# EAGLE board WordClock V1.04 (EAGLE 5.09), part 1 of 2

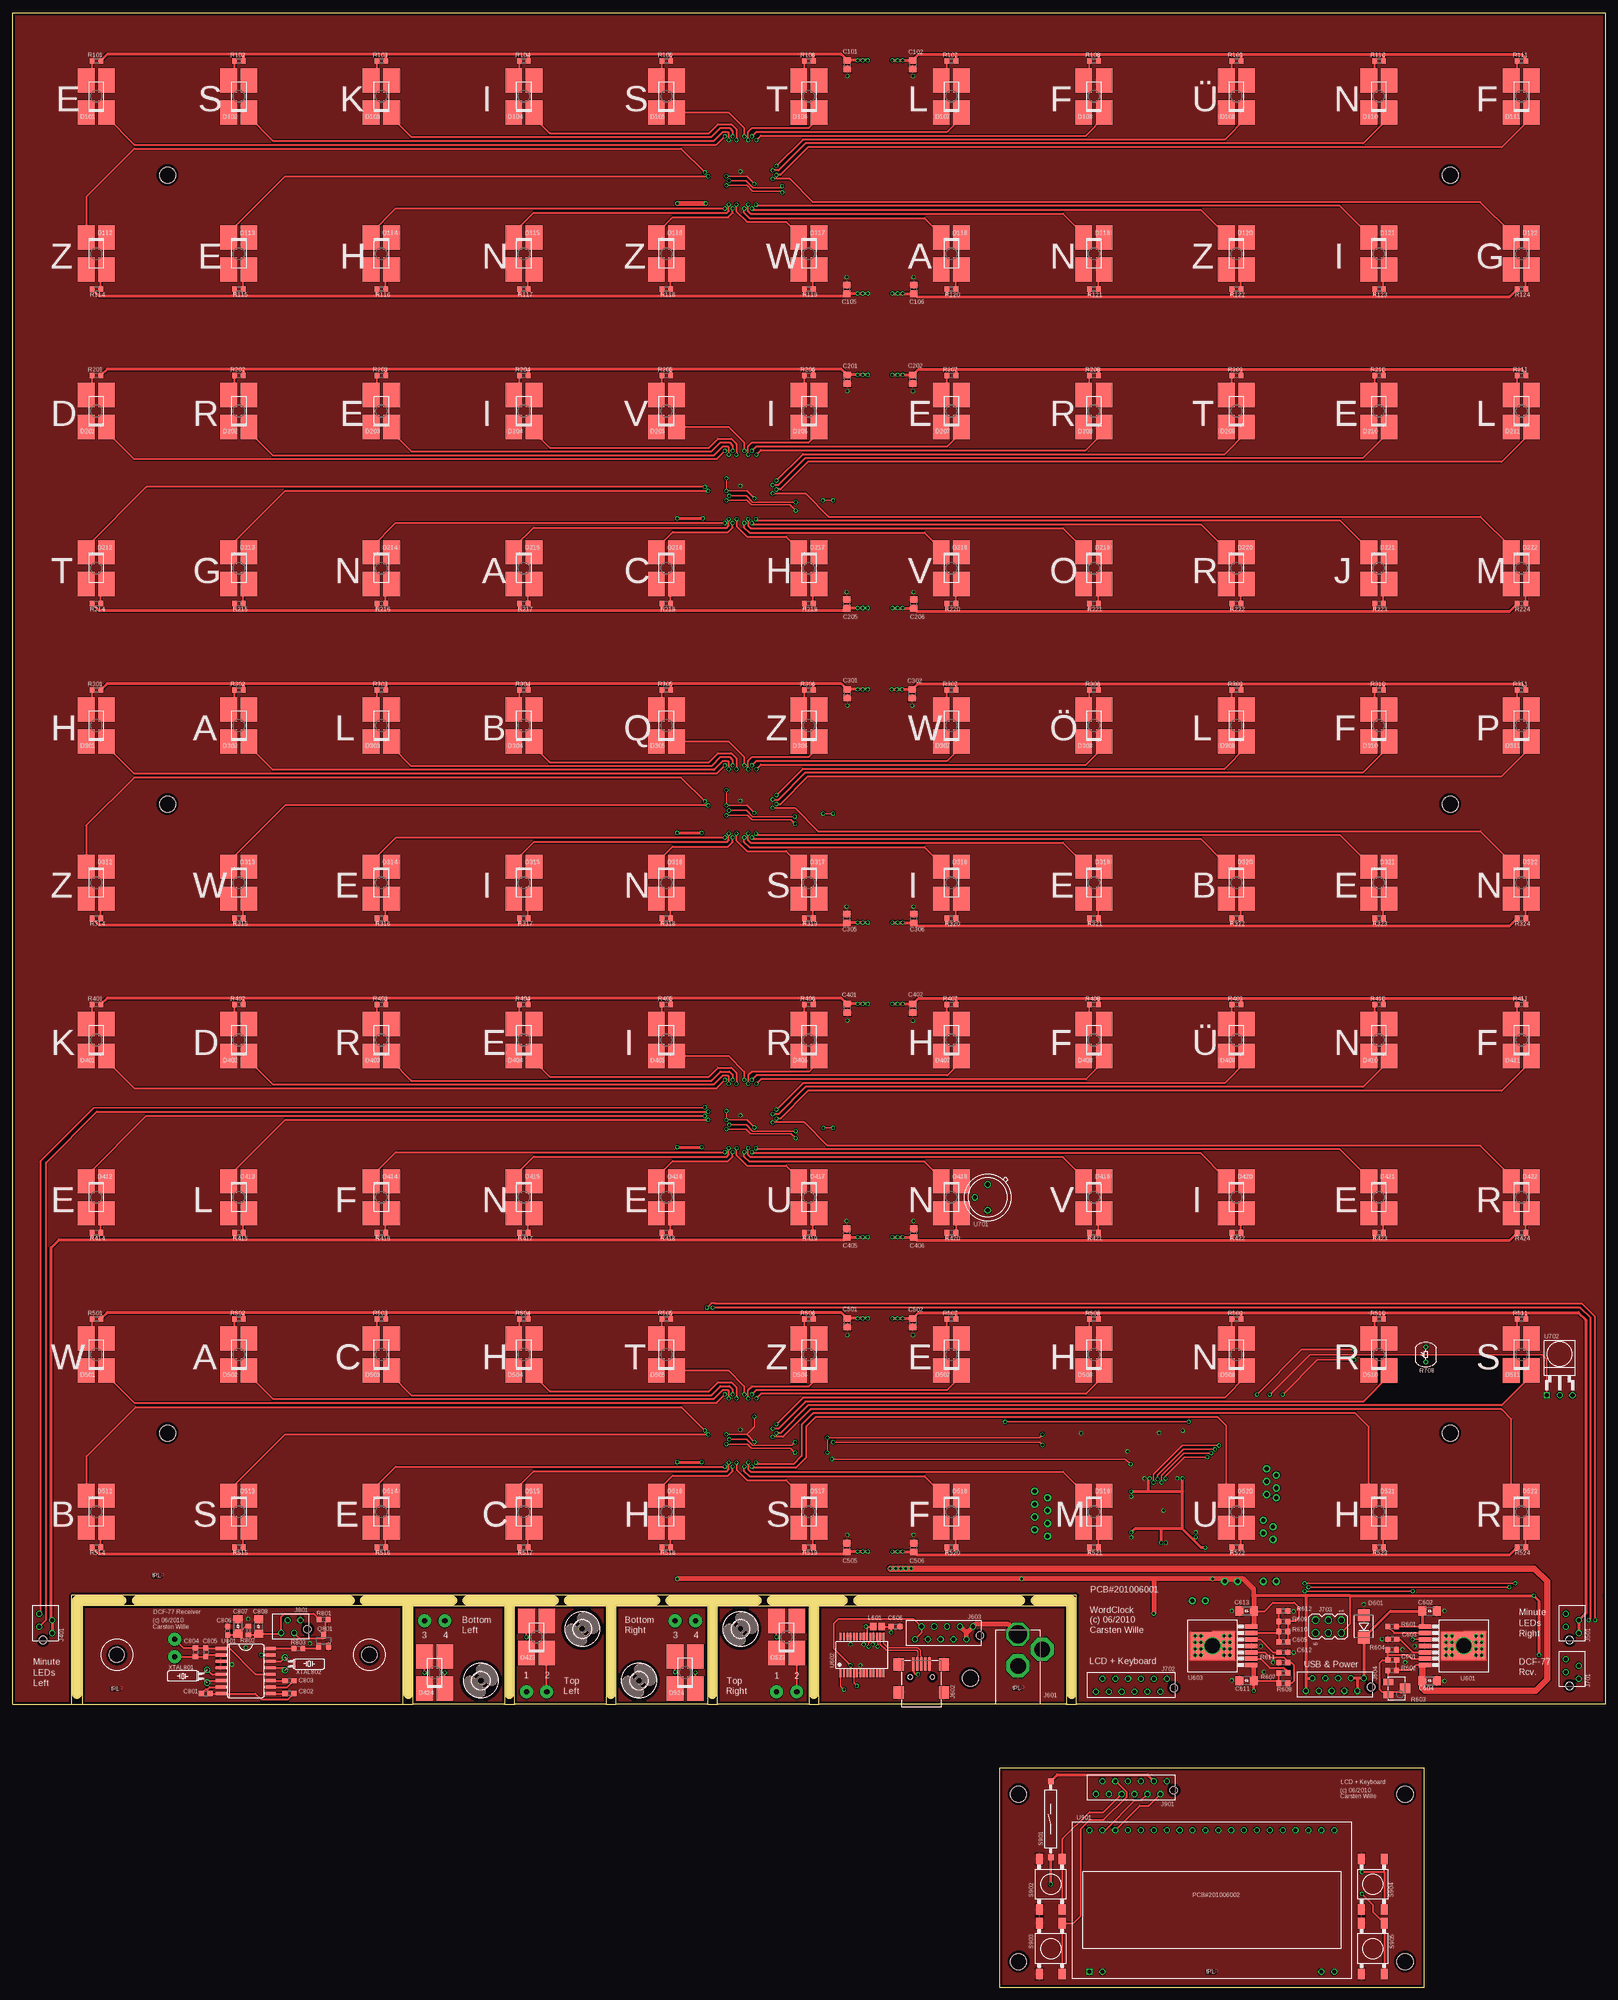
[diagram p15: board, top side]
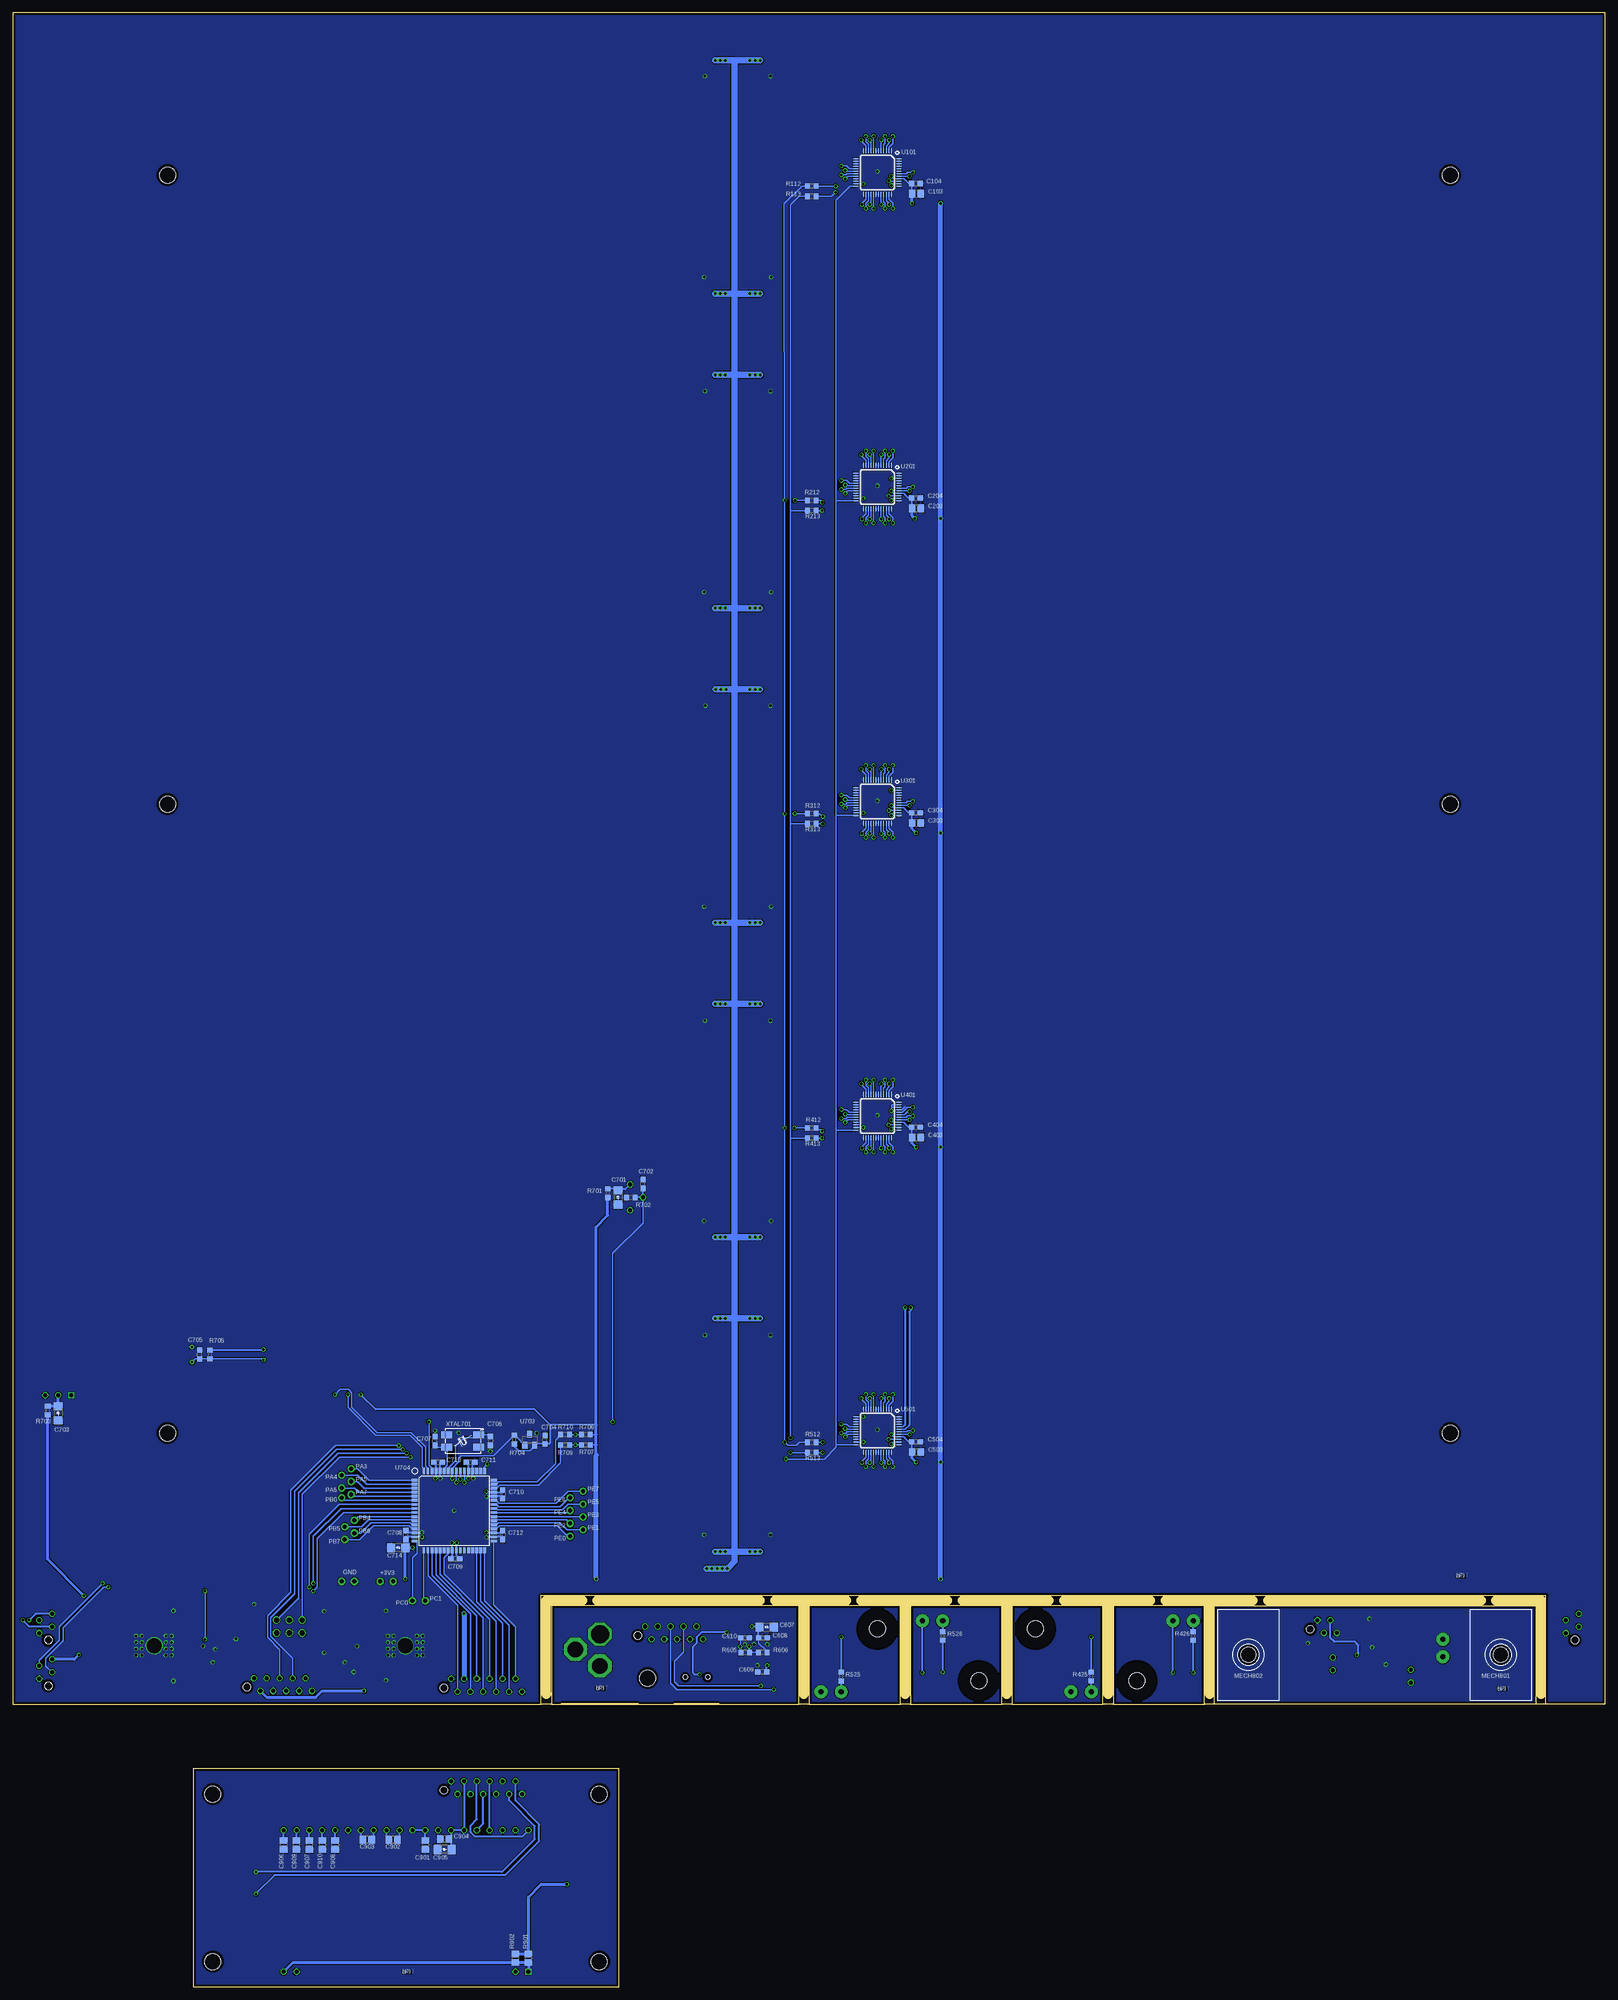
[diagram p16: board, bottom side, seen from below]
Size 314 x 389.24 mm. Coordinates in mm from the lower left corner, seen from the top.
Outline: 194.54,0 278.36,0 278.36,43.18 194.54,43.18 194.54,0
Copper layers (1*16): Top 0.035mm / dielectric 1.5mm / Bottom 0.035mm
Design rules "leiton": minimum track width 6mil, minimum drill 12mil, track to track 6mil, track to pad 6mil, pad to pad 6mil, via to via 6mil, smd to smd 6mil, copper to edge 20mil, drill to drill 8mil, minimum pad ring 8mil, minimum via ring 6mil, stop-mask expansion 3mil, vias tented up to drill 0mil, thermal gap 8mil
Holes 3.2 mm at 188.82,60.96 198.35,38.1 198.35,5.08 274.55,38.1 274.55,5.08

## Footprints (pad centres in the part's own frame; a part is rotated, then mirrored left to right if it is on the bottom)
C0805 = smd 1.3 x 1.5: 1 -0.85,0; 2 0.85,0
C0603 = smd 1.1 x 1: 1 -0.85,0; 2 0.85,0
C1206 = smd 1.6 x 1.8: 1 -1.4,0; 2 1.4,0
P-LCC-2 = smd 3.3 x 4.8: A -2,3.15; C 2,-3.15; NC@0 2,3.15; NC@1 -2,-3.15
SMB = smd 2.4 x 2.4: A 2.2,0; C -2.2,0
3,2 = hole 3.2: 0,0
MICRO-MATCH-4 = drill 0.8 round: 1 -1.905,-1.27; 2 -0.635,1.27; 3 0.635,-1.27; 4 1.905,1.27 | hole 1.5: -3.305,0.53
RAPC722X = drill 3.556 pad 4.572 octagon: 1 0,13.741 | drill 3.048 pad 4.572 octagon: 2 0,7.493; 3 4.801,10.744
USB-MINI-B-SMD = smd 2.6 x 0.5: 1 2.6,1.6; 2 2.6,0.8; 3 2.6,0; 4 2.6,-0.8; 5 2.6,-1.6 | smd 2.5 x 2: S0 -3,4.45; S1 2.5,4.45; S2 2.5,-4.45; S3 -3,-4.45 | hole 0.9: 0,2.2; 0,-2.2
MICRO-MATCH-10 = drill 0.8 round: 1 -5.715,-1.27; 2 -4.445,1.27; 3 -3.175,-1.27; 4 -1.905,1.27; 5 -0.635,-1.27; 6 0.635,1.27; 7 1.905,-1.27; 8 3.175,1.27; 9 4.445,-1.27; 10 5.715,1.27 | hole 1.5: -7.115,0.53
MICRO-MATCH-12 = drill 0.8 round: 1 -6.985,-1.27; 2 -5.715,1.27; 3 -4.445,-1.27; 4 -3.175,1.27; 5 -1.905,-1.27; 6 -0.635,1.27; 7 0.635,-1.27; 8 1.905,1.27; 9 3.175,-1.27; 10 4.445,1.27; 11 5.715,-1.27; 12 6.985,1.27 | hole 1.5: -8.385,0.53
MA03-2 = drill 1.016 round: 1 -1.27,2.54 | drill 1.016 octagon: 2 1.27,2.54; 3 -1.27,0; 4 1.27,0; 5 -1.27,-2.54; 6 1.27,-2.54
L0805 = smd 1.3 x 1.5: 1 -0.85,0; 2 0.85,0
SOCKET = hole 3: 0,0
WORDCLOCK_S = hole 3.2: 281.95,30.5; 29.05,278.5; 29.05,30.5; 281.95,278.5; 29.05,154.5; 281.95,154.5
SOT23 = smd 1 x 1.4: 1 -0.95,-1.1; 2 0.95,-1.1; 3 0,1.1
R0603 = smd 1 x 1.1: 1 -0.85,0; 2 0.85,0
RTRIM3224W = smd 1.3 x 2: 1 -1.25,-1.65; 3 1.25,-1.65 | smd 2 x 2: 2 0,1.65
LDR_A90 = drill 0.5 round: 1 -1.5,0; 2 1.5,0
R0805@1 = smd 1.3 x 1.5: 1 -0.85,0; 2 0.85,0
MK16-X-2 = smd 1.2 x 1.2: 1 -7.5,0; 2 7.5,0
LSH1301 = smd 2.1 x 1.4: 1 -5,2.25; 2 5,2.25; 3 -5,-2.25; 4 5,-2.25
LQFP48 = smd 0.203 x 1: 1 -2.75,-4.25; 2 -2.25,-4.25; 3 -1.75,-4.25; 4 -1.25,-4.25; 5 -0.75,-4.25; 6 -0.25,-4.25; 7 0.25,-4.25; 8 0.75,-4.25; 9 1.25,-4.25; 10 1.75,-4.25; 11 2.25,-4.25; 12 2.75,-4.25; 25 2.75,4.25; 26 2.25,4.25; 27 1.75,4.25; 28 1.25,4.25; 29 0.75,4.25; 30 0.25,4.25; 31 -0.25,4.25; 32 -0.75,4.25; 33 -1.25,4.25; 34 -1.75,4.25; 35 -2.25,4.25; 36 -2.75,4.25 | smd 1 x 0.203: 13 4.25,-2.75; 14 4.25,-2.25; 15 4.25,-1.75; 16 4.25,-1.25; 17 4.25,-0.75; 18 4.25,-0.25; 19 4.25,0.25; 20 4.25,0.75; 21 4.25,1.25; 22 4.25,1.75; 23 4.25,2.25; 24 4.25,2.75; 37 -4.25,2.75; 38 -4.25,2.25; 39 -4.25,1.75; 40 -4.25,1.25; 41 -4.25,0.75; 42 -4.25,0.25; 43 -4.25,-0.25; 44 -4.25,-0.75; 45 -4.25,-1.25; 46 -4.25,-1.75; 47 -4.25,-2.25; 48 -4.25,-2.75
TO-PMOD-7HS = smd 0.89 x 2.41: 1 -3.81,-7.63; 2 -2.54,-7.63; 3 -1.27,-7.63; 4 0,-7.63; 5 1.27,-7.63; 6 2.54,-7.63; 7 3.81,-7.63 | smd 5.35 x 8.54: HS 0,0
SSOP28 = smd 0.4 x 1.5: 1 -4.225,-3.625; 2 -3.575,-3.625; 3 -2.925,-3.625; 4 -2.275,-3.625; 5 -1.625,-3.625; 6 -0.975,-3.625; 7 -0.325,-3.625; 8 0.325,-3.625; 9 0.975,-3.625; 10 1.625,-3.625; 11 2.275,-3.625; 12 2.925,-3.625; 13 3.575,-3.625; 14 4.225,-3.625; 15 4.225,3.625; 16 3.575,3.625; 17 2.925,3.625; 18 2.275,3.625; 19 1.625,3.625; 20 0.975,3.625; 21 0.325,3.625; 22 -0.325,3.625; 23 -0.975,3.625; 24 -1.625,3.625; 25 -2.275,3.625; 26 -2.925,3.625; 27 -3.575,3.625; 28 -4.225,3.625
TO-5 = drill 0.813 octagon: 1 0,-2.54; 2 2.54,0; 3 0,2.54
TSOP322 = drill 0.8 square: 1 -2.54,-2.54 | drill 0.8 round: 2 0,-2.54; 3 2.54,-2.54
TQFP64 = smd 1.194 x 0.559: 1 -7.8,6; 2 -7.8,5.2; 3 -7.8,4.4; 4 -7.8,3.6; 5 -7.8,2.8; 6 -7.8,2; 7 -7.8,1.2; 8 -7.8,0.4; 9 -7.8,-0.4; 10 -7.8,-1.2; 11 -7.8,-2; 12 -7.8,-2.8; 13 -7.8,-3.6; 14 -7.8,-4.4; 15 -7.8,-5.2; 16 -7.8,-6; 33 7.8,-6; 34 7.8,-5.2; 35 7.8,-4.4; 36 7.8,-3.6; 37 7.8,-2.8; 38 7.8,-2; 39 7.8,-1.2; 40 7.8,-0.4; 41 7.8,0.4; 42 7.8,1.2; 43 7.8,2; 44 7.8,2.8; 45 7.8,3.6; 46 7.8,4.4; 47 7.8,5.2; 48 7.8,6 | smd 0.559 x 1.194: 17 -6,-7.8; 18 -5.2,-7.8; 19 -4.4,-7.8; 20 -3.6,-7.8; 21 -2.8,-7.8; 22 -2,-7.8; 23 -1.2,-7.8; 24 -0.4,-7.8; 25 0.4,-7.8; 26 1.2,-7.8; 27 2,-7.8; 28 2.8,-7.8; 29 3.6,-7.8; 30 4.4,-7.8; 31 5.2,-7.8; 32 6,-7.8; 49 6,7.8; 50 5.2,7.8; 51 4.4,7.8; 52 3.6,7.8; 53 2.8,7.8; 54 2,7.8; 55 1.2,7.8; 56 0.4,7.8; 57 -0.4,7.8; 58 -1.2,7.8; 59 -2,7.8; 60 -2.8,7.8; 61 -3.6,7.8; 62 -4.4,7.8; 63 -5.2,7.8; 64 -6,7.8
SO16L = smd 0.66 x 2.032: 1 -4.445,-4.902; 2 -3.175,-4.902; 3 -1.905,-4.902; 4 -0.635,-4.902; 5 0.635,-4.902; 6 1.905,-4.902; 7 3.175,-4.902; 8 4.445,-4.902; 9 4.445,4.902; 10 3.175,4.902; 11 1.905,4.902; 12 0.635,4.902; 13 -0.635,4.902; 14 -1.905,4.902; 15 -3.175,4.902; 16 -4.445,4.902
EA_DOGM132-5 = drill 0.8 square: 1 -24.13,-12.19 | drill 0.8 round: 2 -21.59,-12.19; 19 21.59,-12.19; 20 24.13,-12.19; 21 24.13,15.75; 22 21.59,15.75; 23 19.05,15.75; 24 16.51,15.75; 25 13.97,15.75; 26 11.43,15.75; 27 8.89,15.75; 28 6.35,15.75; 29 3.81,15.75; 30 1.27,15.75; 31 -1.27,15.75; 32 -3.81,15.75; 33 -6.35,15.75; 34 -8.89,15.75; 35 -11.43,15.75; 36 -13.97,15.75; 37 -16.51,15.75; 38 -19.05,15.75; 39 -21.59,15.75; 40 -24.13,15.75
SINGLE-PIN = drill 0.813 pad 1.422 round: P$1 0,0
SINGLE-PIN_BIG = drill 1.016 pad 2.54 round: 1 0,0
MQ = smd 2.2 x 1.4: 1 -3.15,-1.25; 2 3.15,-1.25; 3 3.15,1.25; 4 -3.15,1.25
TC26H = drill 0.813 round: 1 -1.27,0; 2 1.27,0

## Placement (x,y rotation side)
C101  1E-6-1U-0805  [C0805]  164.57,378.99 270 top
C102  1E-6-1U-0805  [C0805]  177.46,378.99 270 top
C103  1E-6-1U-0805  [C0805]  135.81,353.54 0 bottom
C104  1E-9-100N-0603  [C0603]  135.88,355.57 0 bottom
C105  1E-6-1U-0805  [C0805]  164.47,334.69 90 top
C106  1E-6-1U-0805  [C0805]  177.69,334.69 90 top
C201  1E-6-1U-0805  [C0805]  164.57,316.99 270 top
C202  1E-6-1U-0805  [C0805]  177.46,316.99 270 top
C203  1E-6-1U-0805  [C0805]  135.81,291.54 0 bottom
C204  1E-9-100N-0603  [C0603]  135.88,293.57 0 bottom
C205  1E-6-1U-0805  [C0805]  164.47,272.69 90 top
C206  1E-6-1U-0805  [C0805]  177.69,272.69 90 top
C301  1E-6-1U-0805  [C0805]  164.57,254.99 270 top
C302  1E-6-1U-0805  [C0805]  177.33,254.99 270 top
C303  1E-6-1U-0805  [C0805]  135.81,229.54 0 bottom
C304  1E-9-100N-0603  [C0603]  135.88,231.57 0 bottom
C305  1E-6-1U-0805  [C0805]  164.47,210.69 90 top
C306  1E-6-1U-0805  [C0805]  177.69,210.69 90 top
C401  1E-6-1U-0805  [C0805]  164.57,192.99 270 top
C402  1E-6-1U-0805  [C0805]  177.46,192.99 270 top
C403  1E-6-1U-0805  [C0805]  135.81,167.54 0 bottom
C404  1E-9-100N-0603  [C0603]  135.88,169.57 0 bottom
C405  1E-6-1U-0805  [C0805]  164.47,148.69 90 top
C406  1E-6-1U-0805  [C0805]  177.69,148.69 90 top
C501  1E-6-1U-0805  [C0805]  164.57,130.99 270 top
C502  1E-6-1U-0805  [C0805]  177.46,130.99 270 top
C503  1E-6-1U-0805  [C0805]  135.81,105.54 0 bottom
C504  1E-9-100N-0603  [C0603]  135.88,107.57 0 bottom
C505  1E-6-1U-0805  [C0805]  164.47,86.69 90 top
C506  1E-6-1U-0805  [C0805]  177.69,86.69 90 top
C601  1E-9-22N-0603  [C0603]  272.01,64.52 180 top
C602  1E-6-10U-1206  [C1206]  279.38,74.17 0 top
C603  1E-9-22N-0603  [C0603]  272.01,68.58 180 top
C604  1E-6-10U-1206  [C1206]  279.38,60.45 0 top
C605  1E-9-22N-0603  [C0603]  250.55,68.07 180 top
C606  1E-9-10N-0603  [C0603]  174.09,71.12 0 top
C607  1E-6-10U-1206  [C1206]  165.33,70.99 0 bottom
C608  1E-9-100N-0603  [C0603]  166.07,68.91 0 bottom
C609  1E-9-100N-0603  [C0603]  166.19,62.15 180 bottom
C610  1E-9-100N-0603  [C0603]  169.57,68.91 0 bottom
C611  1E-6-10U-1206  [C1206]  243.31,60.45 180 top
C612  1E-9-22N-0603  [C0603]  250.55,66.04 0 top
C613  1E-6-10U-1206  [C1206]  243.31,74.17 180 top
C701  1E-6-10U-1206  [C1206]  194.67,155.7 270 bottom
C702  1E-9-33N-0603  [C0603]  189.71,158.37 90 bottom
C703  1E-6-10U-1206  [C1206]  305.03,113.16 270 bottom
C704  1E-9-100N-0603  [C0603]  209.02,107.95 90 bottom
C705  1E-9-33N-0603  [C0603]  277.14,124.74 90 bottom
C706  1E-12-22P-0603  [C0603]  219.81,107.7 270 bottom
C707  1E-12-22P-0603  [C0603]  230.74,107.7 90 bottom
C708  1E-9-100N-0603  [C0603]  236.48,89.18 90 bottom
C709  1E-9-100N-0603  [C0603]  226.72,84.45 180 bottom
C710  1E-9-100N-0603  [C0603]  217.37,97.18 270 bottom
C711  1E-9-100N-0603  [C0603]  223.72,103.53 0 bottom
C712  1E-9-100N-0603  [C0603]  217.37,89.18 270 bottom
C713  1E-9-100N-0603  [C0603]  230.13,103.53 0 bottom
C714  1E-6-10U-1206  [C1206]  237.97,86.66 180 bottom
C801  1E-9-6.8N-0603  [C0603]  38.08,57.91 0 top
C802  1E-9-33N-0603  [C0603]  54.59,57.91 180 top
C803  1E-9-10N-0603  [C0603]  54.59,60.45 180 top
C804  1E-9-1.5N-0603  [C0603]  36.04,66.04 270 top
C805  1E-9-1.5N-0603  [C0603]  38.08,66.04 270 top
C806  1E-9-100N-0603  [C0603]  42.39,70.31 90 top
C807  1E-6-10U-1206  [C1206]  44.43,71.15 90 top
C808  1E-6-10U-1206  [C1206]  48.49,71.12 90 top
C901  1E-6-1U-0805  [C0805]  232.64,28.07 270 bottom
C902  1E-6-1U-0805  [C0805]  238.99,29.08 180 bottom
C903  1E-6-1U-0805  [C0805]  244.07,29.08 180 bottom
C904  1E-6-1U-0805  [C0805]  228.83,29.21 180 bottom
C905  1E-6-10U-1206  [C1206]  228.83,27.18 180 bottom
C906  1E-6-1U-0805  [C0805]  260.58,28.07 270 bottom
C907  1E-6-1U-0805  [C0805]  255.5,28.07 270 bottom
C908  1E-6-1U-0805  [C0805]  250.42,28.07 270 bottom
C909  1E-6-1U-0805  [C0805]  258.04,28.07 270 bottom
C910  1E-6-1U-0805  [C0805]  252.96,28.07 270 bottom
D101  TOPLED-LUW  [P-LCC-2]  16.5,372.74 0 top
D102  TOPLED-LUW  [P-LCC-2]  44.6,372.74 0 top
D103  TOPLED-LUW  [P-LCC-2]  72.7,372.74 0 top
D104  TOPLED-LUW  [P-LCC-2]  100.8,372.74 0 top
D105  TOPLED-LUW  [P-LCC-2]  128.9,372.74 0 top
D106  TOPLED-LUW  [P-LCC-2]  157,372.74 0 top
D107  TOPLED-LUW  [P-LCC-2]  185.1,372.74 0 top
D108  TOPLED-LUW  [P-LCC-2]  213.2,372.74 0 top
D109  TOPLED-LUW  [P-LCC-2]  241.3,372.74 0 top
D110  TOPLED-LUW  [P-LCC-2]  269.4,372.74 0 top
D111  TOPLED-LUW  [P-LCC-2]  297.5,372.74 0 top
D112  TOPLED-LUW  [P-LCC-2]  16.5,341.74 180 top
D113  TOPLED-LUW  [P-LCC-2]  44.6,341.74 180 top
D114  TOPLED-LUW  [P-LCC-2]  72.7,341.74 180 top
D115  TOPLED-LUW  [P-LCC-2]  100.8,341.74 180 top
D116  TOPLED-LUW  [P-LCC-2]  128.9,341.74 180 top
D117  TOPLED-LUW  [P-LCC-2]  157,341.74 180 top
D118  TOPLED-LUW  [P-LCC-2]  185.1,341.74 180 top
D119  TOPLED-LUW  [P-LCC-2]  213.2,341.74 180 top
D120  TOPLED-LUW  [P-LCC-2]  241.3,341.74 180 top
D121  TOPLED-LUW  [P-LCC-2]  269.4,341.74 180 top
D122  TOPLED-LUW  [P-LCC-2]  297.5,341.74 180 top
D201  TOPLED-LUW  [P-LCC-2]  16.5,310.74 0 top
D202  TOPLED-LUW  [P-LCC-2]  44.6,310.74 0 top
D203  TOPLED-LUW  [P-LCC-2]  72.7,310.74 0 top
D204  TOPLED-LUW  [P-LCC-2]  100.8,310.74 0 top
D205  TOPLED-LUW  [P-LCC-2]  128.9,310.74 0 top
D206  TOPLED-LUW  [P-LCC-2]  157,310.74 0 top
D207  TOPLED-LUW  [P-LCC-2]  185.1,310.74 0 top
D208  TOPLED-LUW  [P-LCC-2]  213.2,310.74 0 top
D209  TOPLED-LUW  [P-LCC-2]  241.3,310.74 0 top
D210  TOPLED-LUW  [P-LCC-2]  269.4,310.74 0 top
D211  TOPLED-LUW  [P-LCC-2]  297.5,310.74 0 top
D212  TOPLED-LUW  [P-LCC-2]  16.5,279.74 180 top
D213  TOPLED-LUW  [P-LCC-2]  44.6,279.74 180 top
D214  TOPLED-LUW  [P-LCC-2]  72.7,279.74 180 top
D215  TOPLED-LUW  [P-LCC-2]  100.8,279.74 180 top
D216  TOPLED-LUW  [P-LCC-2]  128.9,279.74 180 top
D217  TOPLED-LUW  [P-LCC-2]  157,279.74 180 top
D218  TOPLED-LUW  [P-LCC-2]  185.1,279.74 180 top
D219  TOPLED-LUW  [P-LCC-2]  213.2,279.74 180 top
D220  TOPLED-LUW  [P-LCC-2]  241.3,279.74 180 top
D221  TOPLED-LUW  [P-LCC-2]  269.4,279.74 180 top
D222  TOPLED-LUW  [P-LCC-2]  297.5,279.74 180 top
D301  TOPLED-LUW  [P-LCC-2]  16.5,248.74 0 top
D302  TOPLED-LUW  [P-LCC-2]  44.6,248.74 0 top
D303  TOPLED-LUW  [P-LCC-2]  72.7,248.74 0 top
D304  TOPLED-LUW  [P-LCC-2]  100.8,248.74 0 top
D305  TOPLED-LUW  [P-LCC-2]  128.9,248.74 0 top
D306  TOPLED-LUW  [P-LCC-2]  157,248.74 0 top
D307  TOPLED-LUW  [P-LCC-2]  185.1,248.74 0 top
D308  TOPLED-LUW  [P-LCC-2]  213.2,248.74 0 top
D309  TOPLED-LUW  [P-LCC-2]  241.3,248.74 0 top
D310  TOPLED-LUW  [P-LCC-2]  269.4,248.74 0 top
D311  TOPLED-LUW  [P-LCC-2]  297.5,248.74 0 top
D312  TOPLED-LUW  [P-LCC-2]  16.5,217.74 180 top
D313  TOPLED-LUW  [P-LCC-2]  44.6,217.74 180 top
D314  TOPLED-LUW  [P-LCC-2]  72.7,217.74 180 top
D315  TOPLED-LUW  [P-LCC-2]  100.8,217.74 180 top
D316  TOPLED-LUW  [P-LCC-2]  128.9,217.74 180 top
D317  TOPLED-LUW  [P-LCC-2]  157,217.74 180 top
D318  TOPLED-LUW  [P-LCC-2]  185.1,217.74 180 top
D319  TOPLED-LUW  [P-LCC-2]  213.2,217.74 180 top
D320  TOPLED-LUW  [P-LCC-2]  241.3,217.74 180 top
D321  TOPLED-LUW  [P-LCC-2]  269.4,217.74 180 top
D322  TOPLED-LUW  [P-LCC-2]  297.5,217.74 180 top
D401  TOPLED-LUW  [P-LCC-2]  16.5,186.74 0 top
D402  TOPLED-LUW  [P-LCC-2]  44.6,186.74 0 top
D403  TOPLED-LUW  [P-LCC-2]  72.7,186.74 0 top
D404  TOPLED-LUW  [P-LCC-2]  100.8,186.74 0 top
D405  TOPLED-LUW  [P-LCC-2]  128.9,186.74 0 top
D406  TOPLED-LUW  [P-LCC-2]  157,186.74 0 top
D407  TOPLED-LUW  [P-LCC-2]  185.1,186.74 0 top
D408  TOPLED-LUW  [P-LCC-2]  213.2,186.74 0 top
D409  TOPLED-LUW  [P-LCC-2]  241.3,186.74 0 top
D410  TOPLED-LUW  [P-LCC-2]  269.4,186.74 0 top
D411  TOPLED-LUW  [P-LCC-2]  297.5,186.74 0 top
D412  TOPLED-LUW  [P-LCC-2]  16.5,155.74 180 top
D413  TOPLED-LUW  [P-LCC-2]  44.6,155.74 180 top
D414  TOPLED-LUW  [P-LCC-2]  72.7,155.74 180 top
D415  TOPLED-LUW  [P-LCC-2]  100.8,155.74 180 top
D416  TOPLED-LUW  [P-LCC-2]  128.9,155.74 180 top
D417  TOPLED-LUW  [P-LCC-2]  157,155.74 180 top
D418  TOPLED-LUW  [P-LCC-2]  185.1,155.74 180 top
D419  TOPLED-LUW  [P-LCC-2]  213.2,155.74 180 top
D420  TOPLED-LUW  [P-LCC-2]  241.3,155.74 180 top
D421  TOPLED-LUW  [P-LCC-2]  269.4,155.74 180 top
D422  TOPLED-LUW  [P-LCC-2]  297.5,155.74 180 top
D423  TOPLED-LUW  [P-LCC-2]  103.31,69.04 0 top
D424  TOPLED-LUW  [P-LCC-2]  83.21,62.04 0 top
D501  TOPLED-LUW  [P-LCC-2]  16.5,124.74 0 top
D502  TOPLED-LUW  [P-LCC-2]  44.6,124.74 0 top
D503  TOPLED-LUW  [P-LCC-2]  72.7,124.74 0 top
D504  TOPLED-LUW  [P-LCC-2]  100.8,124.74 0 top
D505  TOPLED-LUW  [P-LCC-2]  128.9,124.74 0 top
D506  TOPLED-LUW  [P-LCC-2]  157,124.74 0 top
D507  TOPLED-LUW  [P-LCC-2]  185.1,124.74 0 top
D508  TOPLED-LUW  [P-LCC-2]  213.2,124.74 0 top
D509  TOPLED-LUW  [P-LCC-2]  241.3,124.74 0 top
D510  TOPLED-LUW  [P-LCC-2]  269.4,124.74 0 top
D511  TOPLED-LUW  [P-LCC-2]  297.5,124.74 0 top
D512  TOPLED-LUW  [P-LCC-2]  16.5,93.74 180 top
D513  TOPLED-LUW  [P-LCC-2]  44.6,93.74 180 top
D514  TOPLED-LUW  [P-LCC-2]  72.7,93.74 180 top
D515  TOPLED-LUW  [P-LCC-2]  100.8,93.74 180 top
D516  TOPLED-LUW  [P-LCC-2]  128.9,93.74 180 top
D517  TOPLED-LUW  [P-LCC-2]  157,93.74 180 top
D518  TOPLED-LUW  [P-LCC-2]  185.1,93.74 180 top
D519  TOPLED-LUW  [P-LCC-2]  213.2,93.74 180 top
D520  TOPLED-LUW  [P-LCC-2]  241.3,93.74 180 top
D521  TOPLED-LUW  [P-LCC-2]  269.4,93.74 180 top
D522  TOPLED-LUW  [P-LCC-2]  297.5,93.74 180 top
D523  TOPLED-LUW  [P-LCC-2]  152.61,69.04 0 top
D524  TOPLED-LUW  [P-LCC-2]  132.6,62.06 0 top
D601  20BQ030-SMB  [SMB]  266.42,71.12 90 top
H401  MOUNT-HOLE3.2  [3,2]  92.31,60.44 0 top
H402  MOUNT-HOLE3.2  [3,2]  112.31,70.64 0 top
H501  MOUNT-HOLE3.2  [3,2]  123.51,60.44 0 top
H502  MOUNT-HOLE3.2  [3,2]  143.51,70.64 0 top
J401  MICRO-MATCH-4  [MICRO-MATCH-4]  6.5,71.74 90 top
J501  MICRO-MATCH-4  [MICRO-MATCH-4]  307.5,71.74 90 top
J601  PWR-JACK  [RAPC722X]  198.22,55.88 0 top
J602  USB_B_MINI  [USB-MINI-B-SMD]  179.17,61.14 90 top
J603  MICRO-MATCH-10  [MICRO-MATCH-10]  183.62,69.85 180 top
J604  MICRO-MATCH-10  [MICRO-MATCH-10]  260.71,59.69 180 top
J701  MICRO-MATCH-4  [MICRO-MATCH-4]  307.5,62.74 90 top
J702  MICRO-MATCH-12  [MICRO-MATCH-12]  220.57,59.56 180 top
J703  PROG-PDI  [MA03-2]  259.44,71.12 270 top
J801  MICRO-MATCH-4  [MICRO-MATCH-4]  54.84,71.12 180 top
J901  MICRO-MATCH-12  [MICRO-MATCH-12]  220.57,39.37 180 top
L601  L-1U0-0805  [L0805]  170.54,71.12 180 top
MECH801  SOCKET  [SOCKET]  20.55,65.53 0 bottom
MECH802  SOCKET  [SOCKET]  70.33,65.53 0 bottom
PCB1  PCB-WORDCLOCK-ALL-IN-ONE  [WORDCLOCK_S]  1.5,78.74 0 top
Q801  BC847  [SOT23]  61.32,68.33 0 top
R101  1E0-3,0R-0603  [R0603]  16.5,379.74 180 top
R102  1E0-3,0R-0603  [R0603]  44.6,379.74 180 top
R103  1E0-3,0R-0603  [R0603]  72.7,379.74 180 top
R104  1E0-3,0R-0603  [R0603]  100.8,379.74 180 top
R105  1E0-3,0R-0603  [R0603]  128.9,379.74 180 top
R106  1E0-3,0R-0603  [R0603]  157,379.74 180 top
R107  1E0-3,0R-0603  [R0603]  185.1,379.74 180 top
R108  1E0-3,0R-0603  [R0603]  213.2,379.74 180 top
R109  1E0-3,0R-0603  [R0603]  241.3,379.74 180 top
R110  1E0-3,0R-0603  [R0603]  269.4,379.74 180 top
R111  1E0-3,0R-0603  [R0603]  297.5,379.74 180 top
R112  1E2-330R-0603  [R0603]  156.44,355.07 0 bottom
R113  1E2-330R-0603  [R0603]  156.44,353.06 0 bottom
R114  1E0-3,0R-0603  [R0603]  16.5,334.74 180 top
R115  1E0-3,0R-0603  [R0603]  44.6,334.74 180 top
R116  1E0-3,0R-0603  [R0603]  72.7,334.74 180 top
R117  1E0-3,0R-0603  [R0603]  100.8,334.74 180 top
R118  1E0-3,0R-0603  [R0603]  128.9,334.74 180 top
R119  1E0-3,0R-0603  [R0603]  157,334.74 180 top
R120  1E0-3,0R-0603  [R0603]  185.1,334.74 180 top
R121  1E0-3,0R-0603  [R0603]  213.2,334.74 180 top
R122  1E0-3,0R-0603  [R0603]  241.3,334.74 180 top
R123  1E0-3,0R-0603  [R0603]  269.4,334.74 180 top
R124  1E0-3,0R-0603  [R0603]  297.5,334.74 180 top
R201  1E0-3,0R-0603  [R0603]  16.5,317.74 180 top
R202  1E0-3,0R-0603  [R0603]  44.6,317.74 180 top
R203  1E0-3,0R-0603  [R0603]  72.7,317.74 180 top
R204  1E0-3,0R-0603  [R0603]  100.8,317.74 180 top
R205  1E0-3,0R-0603  [R0603]  128.9,317.74 180 top
R206  1E0-3,0R-0603  [R0603]  157,317.74 180 top
R207  1E0-3,0R-0603  [R0603]  185.1,317.74 180 top
R208  1E0-3,0R-0603  [R0603]  213.2,317.74 180 top
R209  1E0-3,0R-0603  [R0603]  241.3,317.74 180 top
R210  1E0-3,0R-0603  [R0603]  269.4,317.74 180 top
R211  1E0-3,0R-0603  [R0603]  297.5,317.74 180 top
R212  1E2-330R-0603  [R0603]  156.44,293.12 0 bottom
R213  1E2-330R-0603  [R0603]  156.44,291.08 0 bottom
R214  1E0-3,0R-0603  [R0603]  16.5,272.74 180 top
R215  1E0-3,0R-0603  [R0603]  44.6,272.74 180 top
R216  1E0-3,0R-0603  [R0603]  72.7,272.74 180 top
R217  1E0-3,0R-0603  [R0603]  100.8,272.74 180 top
R218  1E0-3,0R-0603  [R0603]  128.9,272.74 180 top
R219  1E0-3,0R-0603  [R0603]  157,272.74 180 top
R220  1E0-3,0R-0603  [R0603]  185.1,272.74 180 top
R221  1E0-3,0R-0603  [R0603]  213.2,272.74 180 top
R222  1E0-3,0R-0603  [R0603]  241.3,272.74 180 top
R223  1E0-3,0R-0603  [R0603]  269.4,272.74 180 top
R224  1E0-3,0R-0603  [R0603]  297.5,272.74 180 top
R301  1E0-3,0R-0603  [R0603]  16.5,255.74 180 top
R302  1E0-3,0R-0603  [R0603]  44.6,255.74 180 top
R303  1E0-3,0R-0603  [R0603]  72.7,255.74 180 top
R304  1E0-3,0R-0603  [R0603]  100.8,255.74 180 top
R305  1E0-3,0R-0603  [R0603]  128.9,255.74 180 top
R306  1E0-3,0R-0603  [R0603]  157,255.74 180 top
R307  1E0-3,0R-0603  [R0603]  185.1,255.74 180 top
R308  1E0-3,0R-0603  [R0603]  213.2,255.74 180 top
R309  1E0-3,0R-0603  [R0603]  241.3,255.74 180 top
R310  1E0-3,0R-0603  [R0603]  269.4,255.74 180 top
R311  1E0-3,0R-0603  [R0603]  297.5,255.74 180 top
R312  1E2-330R-0603  [R0603]  156.44,231.37 0 bottom
R313  1E2-330R-0603  [R0603]  156.44,229.36 0 bottom
R314  1E0-3,0R-0603  [R0603]  16.5,210.74 180 top
R315  1E0-3,0R-0603  [R0603]  44.6,210.74 180 top
R316  1E0-3,0R-0603  [R0603]  72.7,210.74 180 top
R317  1E0-3,0R-0603  [R0603]  100.8,210.74 180 top
R318  1E0-3,0R-0603  [R0603]  128.9,210.74 180 top
R319  1E0-3,0R-0603  [R0603]  157,210.74 180 top
R320  1E0-3,0R-0603  [R0603]  185.1,210.74 180 top
R321  1E0-3,0R-0603  [R0603]  213.2,210.74 180 top
R322  1E0-3,0R-0603  [R0603]  241.3,210.74 180 top
R323  1E0-3,0R-0603  [R0603]  269.4,210.74 180 top
R324  1E0-3,0R-0603  [R0603]  297.5,210.74 180 top
R401  1E0-3,0R-0603  [R0603]  16.5,193.74 180 top
R402  1E0-3,0R-0603  [R0603]  44.6,193.74 180 top
R403  1E0-3,0R-0603  [R0603]  72.7,193.74 180 top
R404  1E0-3,0R-0603  [R0603]  100.8,193.74 180 top
R405  1E0-3,0R-0603  [R0603]  128.9,193.74 180 top
R406  1E0-3,0R-0603  [R0603]  157,193.74 180 top
R407  1E0-3,0R-0603  [R0603]  185.1,193.74 180 top
R408  1E0-3,0R-0603  [R0603]  213.2,193.74 180 top
R409  1E0-3,0R-0603  [R0603]  241.3,193.74 180 top
R410  1E0-3,0R-0603  [R0603]  269.4,193.74 180 top
R411  1E0-3,0R-0603  [R0603]  297.5,193.74 180 top
R412  1E2-330R-0603  [R0603]  156.44,169.42 0 bottom
R413  1E2-330R-0603  [R0603]  156.44,167.39 0 bottom
R414  1E0-3,0R-0603  [R0603]  16.5,148.74 180 top
R415  1E0-3,0R-0603  [R0603]  44.6,148.74 180 top
R416  1E0-3,0R-0603  [R0603]  72.7,148.74 180 top
R417  1E0-3,0R-0603  [R0603]  100.8,148.74 180 top
R418  1E0-3,0R-0603  [R0603]  128.9,148.74 180 top
R419  1E0-3,0R-0603  [R0603]  157,148.74 180 top
R420  1E0-3,0R-0603  [R0603]  185.1,148.74 180 top
R421  1E0-3,0R-0603  [R0603]  213.2,148.74 180 top
R422  1E0-3,0R-0603  [R0603]  241.3,148.74 180 top
R423  1E0-3,0R-0603  [R0603]  269.4,148.74 180 top
R424  1E0-3,0R-0603  [R0603]  297.5,148.74 180 top
R425  1E0-3,0R-0603  [R0603]  101.31,61.24 90 bottom
R426  1E0-3,0R-0603  [R0603]  81.21,69.24 270 bottom
R501  1E0-3,0R-0603  [R0603]  16.5,131.74 180 top
R502  1E0-3,0R-0603  [R0603]  44.6,131.74 180 top
R503  1E0-3,0R-0603  [R0603]  72.7,131.74 180 top
R504  1E0-3,0R-0603  [R0603]  100.8,131.74 180 top
R505  1E0-3,0R-0603  [R0603]  128.9,131.74 180 top
R506  1E0-3,0R-0603  [R0603]  157,131.74 180 top
R507  1E0-3,0R-0603  [R0603]  185.1,131.74 180 top
R508  1E0-3,0R-0603  [R0603]  213.2,131.74 180 top
R509  1E0-3,0R-0603  [R0603]  241.3,131.74 180 top
R510  1E0-3,0R-0603  [R0603]  269.4,131.74 180 top
R511  1E0-3,0R-0603  [R0603]  297.5,131.74 180 top
R512  1E2-330R-0603  [R0603]  156.44,107.44 0 bottom
R513  1E2-330R-0603  [R0603]  156.44,105.41 0 bottom
R514  1E0-3,0R-0603  [R0603]  16.5,86.74 180 top
R515  1E0-3,0R-0603  [R0603]  44.6,86.74 180 top
R516  1E0-3,0R-0603  [R0603]  72.7,86.74 180 top
R517  1E0-3,0R-0603  [R0603]  100.8,86.74 180 top
R518  1E0-3,0R-0603  [R0603]  128.9,86.74 180 top
R519  1E0-3,0R-0603  [R0603]  157,86.74 180 top
R520  1E0-3,0R-0603  [R0603]  185.1,86.74 180 top
R521  1E0-3,0R-0603  [R0603]  213.2,86.74 180 top
R522  1E0-3,0R-0603  [R0603]  241.3,86.74 180 top
R523  1E0-3,0R-0603  [R0603]  269.4,86.74 180 top
R524  1E0-3,0R-0603  [R0603]  297.5,86.74 180 top
R525  1E0-3,0R-0603  [R0603]  150.59,61.23 90 bottom
R526  1E0-3,0R-0603  [R0603]  130.61,69.24 270 bottom
R601  1E4-56K-0603  [R0603]  272.01,71.12 180 top
R602  1E3-3,3K-0603  [R0603]  272.01,62.48 180 top
R603  R-TRIM1K-3224W  [RTRIM3224W]  272.9,58.93 270 top
R604  1E3-1,1K-0603  [R0603]  272.01,66.55 0 top
R605  1E4-10K-0603  [R0603]  169.57,66.04 0 bottom
R606  1E3-4,7K-0603  [R0603]  166.12,66.04 180 bottom
R607  1E4-47K-0603  [R0603]  250.55,61.98 0 top
R608  1E4-33K-0603  [R0603]  250.55,59.94 0 top
R609  1E4-13K-0603  [R0603]  250.55,72.14 180 top
R610  1E3-4,7K-0603  [R0603]  250.55,70.1 180 top
R611  1E4-12K-0603  [R0603]  250.55,64.01 180 top
R612  1E3-1,1K-0603  [R0603]  250.55,74.17 0 top
R701  1E2-100R-0603  [R0603]  196.67,156.54 90 bottom
R702  1E4-47K-0603  [R0603]  192.13,155.7 180 bottom
R703  1E2-100R-0603  [R0603]  307.09,113.72 90 bottom
R704  1E4-10K-0603  [R0603]  215.11,107.95 90 bottom
R705  1E4-10K-0603  [R0603]  275.13,124.74 270 bottom
R706  1E3-3,3K-0603  [R0603]  201.02,108.94 180 bottom
R707  1E3-3,3K-0603  [R0603]  201.02,106.91 180 bottom
R708  LDR  [LDR_A90]  278.64,124.74 90 top
R709  1E2-330R-0603  [R0603]  205.08,106.91 180 bottom
R710  1E2-330R-0603  [R0603]  205.08,108.94 180 bottom
R801  1E4-10K-0603  [R0603]  61.32,72.52 0 top
R802  1E2-100R-0603  [R0603]  46.46,70.31 270 top
R803  1E5-100K-0603  [R0603]  56.36,66.8 0 top
R901  1E0-3,3R-0805  [R0805@1]  212.32,5.71 270 bottom
R902  1E0-3,3R-0805  [R0805@1]  214.86,5.71 270 bottom
S901  MK16-SERIES  [MK16-X-2]  204.7,33.15 90 top
S902  LSH1301-9,5  [LSH1301]  204.7,20.32 90 top
S903  LSH1301-9,5  [LSH1301]  204.7,7.62 90 top
S904  LSH1301-9,5  [LSH1301]  268.2,20.32 90 top
S905  LSH1301-9,5  [LSH1301]  268.2,7.62 90 top
U101  PCA9626  [LQFP48]  143.5,357.74 180 bottom
U201  PCA9626  [LQFP48]  143.5,295.74 180 bottom
U301  PCA9626  [LQFP48]  143.5,233.74 180 bottom
U401  PCA9626  [LQFP48]  143.5,171.74 180 bottom
U501  PCA9626  [LQFP48]  143.5,109.74 180 bottom
U601  LMZ12003  [TO-PMOD-7HS]  286.11,67.31 270 top
U602  FT232RL  [SSOP28]  167.49,65.53 0 top
U603  LMZ12003  [TO-PMOD-7HS]  236.58,67.31 90 top
U701  LHI1128  [TO-5]  192.25,155.7 180 top
U702  TSOP32236  [TSOP322]  305.03,119.25 0 top
U703  MCP120  [SOT23]  212.07,107.95 0 bottom
U704  XMEGA64A3  [TQFP64]  226.93,93.98 0 bottom
U801  U4224B  [SO16L]  45.95,62.36 270 top
U901  EA_DOGM132B-5  [EA_DOGM132-5]  236.45,15.24 0 top
X1  SINGLE-PIN-36MIL  [SINGLE-PIN]  204.06,88.9 180 top
X2  SINGLE-PIN-36MIL  [SINGLE-PIN]  201.53,90.17 180 top
X3  SINGLE-PIN-36MIL  [SINGLE-PIN]  204.06,91.44 180 top
X4  SINGLE-PIN-36MIL  [SINGLE-PIN]  201.53,92.71 180 top
X5  SINGLE-PIN-36MIL  [SINGLE-PIN]  204.06,93.98 180 top
X6  SINGLE-PIN-36MIL  [SINGLE-PIN]  201.53,95.25 180 top
X7  SINGLE-PIN-36MIL  [SINGLE-PIN]  204.06,96.52 180 top
X8  SINGLE-PIN-36MIL  [SINGLE-PIN]  201.53,97.79 180 top
X9  SINGLE-PIN-36MIL  [SINGLE-PIN]  247.25,102.23 0 top
X10  SINGLE-PIN-36MIL  [SINGLE-PIN]  249.15,100.97 0 top
X11  SINGLE-PIN-36MIL  [SINGLE-PIN]  247.25,99.69 0 top
X12  SINGLE-PIN-36MIL  [SINGLE-PIN]  249.15,98.42 0 top
X13  SINGLE-PIN-36MIL  [SINGLE-PIN]  247.25,97.16 0 top
X14  SINGLE-PIN-36MIL  [SINGLE-PIN]  249.15,96.52 0 top
X15  SINGLE-PIN-36MIL  [SINGLE-PIN]  246.61,92.07 0 top
X16  SINGLE-PIN-36MIL  [SINGLE-PIN]  248.51,90.8 0 top
X17  SINGLE-PIN-36MIL  [SINGLE-PIN]  246.61,89.53 0 top
X18  SINGLE-PIN-36MIL  [SINGLE-PIN]  248.51,88.27 0 top
X19  SINGLE-PIN-36MIL  [SINGLE-PIN]  235.18,76.2 0 top
X20  SINGLE-PIN-36MIL  [SINGLE-PIN]  232.64,76.2 0 top
X21  SINGLE-PIN-36MIL  [SINGLE-PIN]  246.61,80.01 90 top
X22  SINGLE-PIN-36MIL  [SINGLE-PIN]  249.15,80.01 90 top
X23  SINGLE-PIN-36MIL  [SINGLE-PIN]  241.53,80.01 90 top
X24  SINGLE-PIN-36MIL  [SINGLE-PIN]  238.99,80.01 90 top
X401  SINGLE-PIN-40MIL  [SINGLE-PIN_BIG]  101.31,58.24 90 top
X402  SINGLE-PIN-40MIL  [SINGLE-PIN_BIG]  81.21,72.24 90 top
X403  SINGLE-PIN-40MIL  [SINGLE-PIN_BIG]  105.31,58.24 90 top
X404  SINGLE-PIN-40MIL  [SINGLE-PIN_BIG]  85.21,72.24 90 top
X501  SINGLE-PIN-40MIL  [SINGLE-PIN_BIG]  150.61,58.24 90 top
X502  SINGLE-PIN-40MIL  [SINGLE-PIN_BIG]  130.61,72.24 90 top
X503  SINGLE-PIN-40MIL  [SINGLE-PIN_BIG]  154.61,58.24 90 top
X504  SINGLE-PIN-40MIL  [SINGLE-PIN_BIG]  134.61,72.24 90 top
X801  SINGLE-PIN-40MIL  [SINGLE-PIN_BIG]  31.98,68.58 270 top
X802  SINGLE-PIN-40MIL  [SINGLE-PIN_BIG]  31.98,65.15 270 top
XTAL701  MQ-8.000  [MQ]  225.27,107.7 180 bottom
XTAL801  TC26-77.5  [TC26H]  38.33,61.34 90 top
XTAL802  TC26-77.5  [TC26H]  53.7,63.75 270 top

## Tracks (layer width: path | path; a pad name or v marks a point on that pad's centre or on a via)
12V0  (via drill 0.5)
  Top 0.406: 244.71,63.37 244.33,63.37 U603.1 | 249.7,60.45 R608.1 | 249.7,60.45 R607.1 | C611.1 249.7,60.45 | R601.1 277.98,71.12 U601.1
  Top 0.61: 265.15,60.96 J604.2 | 265.15,60.96 J604.3 | 265.15,60.96 J604.1 D601.C 271.67,74.17 C602.1 277.98,71.12 | v244.71,58.42 C611.1
  Top 0.813: C611.1
  Top 1.016: C611.1 244.71,63.37
  Bottom 0.61: J604.2 263.88,57.15 254.23,57.15 252.96,58.42 v244.71,58.42
+3V3  (via drill 0.5)
  Top 0.254: v140.74,357 144.76,357 v146.26,355.49 | v146.26,293.49 144.76,295 v140.74,295 v140.74,297.43 | v146.26,231.49 144.76,233 v140.74,233 v140.74,235.97 | v146.26,169.49 144.76,171 v140.74,171 v140.74,172.75 | v140.74,109 144.76,109 | 144.76,109 v146.26,107.49 | v146.25,112.5 146.25,110.5 144.76,109 | X24.P$1 X23.P$1 241.53,80.52
  Top 0.406: C605.1 R610.1 R609.1 252.96,72.14 253.59,72.77 253.59,74.93 252.71,75.82 248.51,75.82 246.86,74.17 C613.1 | 244.71,71.5 244.59,71.5 U603.7 | v220.57,97.71 220.55,97.74 | 223.9,99.8 223.9,100.05 v224.18,100.33 | v264.52,125.73 254.23,125.73 v245.34,116.84 | J703.2 263.75,71.63 263.75,77.22
  Top 0.61: v131.04,289.56 v136.12,289.56 | v131.04,227.58 v135.87,227.58 | v131.04,165.61 v135.87,165.61 | v131.04,103.5 v135.87,103.5 | 254.99,77.22 263.75,77.22 v299.95,77.22 300.97,76.2 v300.97,65.53 | 254.99,77.22 244.71,77.22 | v235.16,86.66 234.37,86.66 232.78,88.25 | 230.66,97.71 v230.66,100.33 230.66,100.34 | 223.9,97.71 223.9,99.8 | 223.9,97.71 v220.57,97.71 | 230.66,97.71 223.9,97.71 | 232.78,88.25 230.66,90.37 | 230.66,90.37 230.66,97.71 | v220.57,89.69 221.26,90.37 226.42,90.37 | 230.66,90.37 226.42,90.37 | 226.42,90.37 v226.42,87.63 | 232.78,88.25 v233.28,88.72 | 254.99,77.22 254.99,60.96 | 254.99,60.96 J604.10 | 254.99,60.96 J604.9
  Top 1.016: v131.04,351.66 v136.65,351.66 | 225.02,80.52 v198.96,80.52 v131.04,80.52 | 225.02,80.52 v225.02,73.66 | 225.02,80.52 v236.58,80.52 241.53,80.52 242.67,80.52 244.71,78.49 244.71,77.22 C613.1 244.71,71.5
  Bottom 0.254: 138.15,356.36 138.28,356.49 U101.40 140.24,356.49 v140.74,357 | v146.26,355.49 U101.23 | 138.15,294.36 138.28,294.49 U201.40 140.24,294.49 v140.74,295 | v146.26,293.49 U201.23 | 138.15,232.36 138.28,232.49 U301.40 140.24,232.49 v140.74,233 | v146.26,231.49 U301.23 | 138.15,170.36 138.28,170.49 U401.40 140.24,170.49 v140.74,171 | v146.26,169.49 U401.23 | 138.15,108.36 138.28,108.49 U501.40 140.24,108.49 v140.74,109 | v146.26,107.49 U501.23 | U501.13 146.51,112.49 v146.25,112.5 | U401.47 140.49,173.99 140.74,173.74 140.74,173.49 | v140.74,235.97 140.67,235.99 U301.47 | U201.46 140.64,297.49 v140.74,297.43 | R704.1 215.11,106.68 214.22,105.79 211.94,105.79 211.12,106.61 U703.2 | R706.1 198.99,108.94 198.96,108.97 | R707.1 198.99,106.91 198.96,106.93 | 140.74,173.49 U401.46 | v140.74,172.75 140.74,173.49
  Bottom 0.406: 138.15,356.36 137.36,355.57 C104.1 136.66,355.5 C103.1 | 138.15,294.36 137.36,293.57 C204.1 136.66,293.5 C203.1 | 138.15,232.36 137.36,231.57 C304.1 136.66,231.5 C303.1 | 138.15,170.36 137.36,169.57 C404.1 136.66,169.5 C403.1 | 138.15,108.36 137.36,107.57 C504.1 136.66,107.49 C503.1 | U703.2 210.87,107.1 C704.1 208.22,107.1 208,107.31 208,110.87 | 198.96,110.87 208,110.87 | 208,110.87 211.05,113.92 242.42,113.92 v245.34,116.84 | C710.1 217.38,97.58 U704.45 220.44,97.58 v220.57,97.71 | C712.1 217.38,89.58 U704.35 220.47,89.58 v220.57,89.69 | C709.1 225.87,84.6 226.53,85.25 U704.25 226.53,87.52 v226.42,87.63 | C708.1 236.47,88.78 U704.15 233.36,88.78 v233.28,88.72 | C711.1 224.12,103.53 U704.53 224.12,100.33 v224.18,100.33 | C713.1 230.53,103.53 U704.61 230.53,100.46 v230.66,100.33 | R705.1 264.66,125.59 v264.52,125.73
  Bottom 0.61: v136.65,351.66 C103.1 | C203.1 136.66,290.1 v136.12,289.56 | C303.1 136.66,228.37 v135.87,227.58 | C403.1 136.66,166.4 v135.87,165.61 | C503.1 136.66,104.29 v135.87,103.5 | R701.1 196.67,152.17 198.99,149.86 198.96,110.87 198.96,108.97 198.96,106.93 198.96,104.9 | v300.97,65.53 301.85,64.64 J701.4 | v299.95,77.22 307.09,84.35 R703.1 | 236.42,86.66 v235.16,86.66 | 236.42,86.66 C714.1 | 236.42,86.66 236.58,86.51 v236.58,80.52
  Bottom 1.016: v131.04,351.66 v131.04,289.56 v131.04,227.58 v131.04,165.61 v131.04,103.5 v131.04,80.52 | v198.96,80.52 198.96,104.9 | v225.02,73.66 J702.3
+3V3A  (via drill 0.5)
  Top 0.406: J603.10 179.17,69.85 J603.9 177.65,72.64 162.79,72.64 161.9,71.75 161.9,66.78 v165.2,63.47 165.21,63.36 U602.4
  Bottom 0.406: C609.1 165.34,63.23 v165.2,63.47
A0
  Top 0.406: U901.38 222.22,35.81 224,35.81 J901.2
A+
  Bottom 0.61: U901.1 R901.2 R902.2 258.76,4.86 U901.20
BL
  Top 0.406: S903.3 S903.4 209.14,12.62 210.62,14.1 210.62,31.24 212.4,33.02 215.11,33.02 219.68,37.59 219.68,38.48 217.52,40.64 J901.9
BR  (via drill 0.5)
  Top 0.406: v266.04,18.41 268.2,16.26 268.2,14.87 S905.4 S905.3
  Bottom 0.406: J901.11 214.86,36.83 210.16,32.13 210.16,28.83 216.89,22.1 262.36,22.1 v266.04,18.41
CLK
  Bottom 0.406: U901.37 J901.7
CS#
  Bottom 0.406: U901.40 213.59,29.72 222.81,29.72 223.7,30.61 223.7,31.88 222.48,33.1 J901.5
D+
  Top 0.254: U602.15 171.71,67.78 172.57,66.93 178.54,66.93 179.05,66.42 179.05,65.41 179.17,65.28 J602.3
D-
  Top 0.254: U602.16 171.06,67.67 172.31,66.42 178.28,66.42 178.54,66.17 178.54,65.41 178.37,65.24 J602.2
DCF77  (via drill 0.5)
  Top 0.254: v255.5,78.87 v295.12,78.87
  Bottom 0.254: J701.2 307.44,63.32 307.44,64.9 304.01,68.33 304.01,70.87 296.01,78.87 v295.12,78.87 | v255.5,78.87 255.5,89.27 249.59,95.18 U704.7
DIN
  Bottom 0.406: J901.6 221.21,32.26 U901.36
DISP-A0
  Bottom 0.254: J702.2 226.29,75.31 232.12,81.15 U704.18
DISP-CLK
  Bottom 0.254: J702.7 219.94,72.52 228.96,81.53 228.96,84.63 228.12,85.46 U704.23
DISP-CS#
  Bottom 0.254: J702.5 222.48,73.28 230.53,81.32 U704.20
DISP-DIN
  Bottom 0.254: J702.6 221.21,72.9 229.72,81.41 U704.21
DISP-RESET#
  Bottom 0.254: J702.4 223.75,73.66 231.32,81.23 U704.19
GND  (via drill 0.5, 3)
  Top 0.406: U601.HS 286.11,70.05 290.48,70.05 290.48,64.54 281.76,64.54 281.76,70.05 286.03,70.05 | U603.HS 236.58,70.05 240.92,70.05 240.92,64.57 232.23,64.57 232.23,70.03 236.53,70.03
  Bottom 0.254: U401.45 138.64,172.99 138.03,173.61
  Bottom 0.406: C710.2 217.38,96.78 U704.44 220.52,96.78 v220.57,96.72 | C712.2 217.38,88.78 U704.34 220.49,88.78 v220.57,88.7 | C709.2 227.32,84.45 U704.24 227.32,87.57 v227.38,87.63 | C708.2 236.47,89.58 U704.14 233.38,89.58 v233.28,89.69 | C711.2 223.32,103.53 U704.52 223.32,100.33 v223.17,100.33 | C713.2 229.72,103.53 U704.60 229.72,100.41 v229.64,100.33
  other vias: 219.81,105.66 230.74,109.73 226.04,109.3 210.67,109.22 226.93,93.98 164.57,89.2 177.65,89.2 177.52,128.57 164.57,128.57 164.44,151.05 177.65,151.05 164.57,190.55 177.52,190.55 177.65,213.03 164.44,213.03 164.44,275.01 177.4,252.65 177.65,275.01 164.57,252.65 164.57,314.63 177.52,314.63 164.44,337.11 177.65,337.11 164.57,376.73 177.52,376.73 143.49,357.94 143.49,295.96 143.49,233.86 143.49,171.88 143.49,109.91 240.39,74.22 246.1,67.23 248.51,64.06 240.39,60.5 252.58,74.09 252.58,65.96 266.42,75.49 269.98,68.63 274.04,66.6 276.45,67.23 282.3,60.38 282.3,74.22 246.74,62.15 274.55,64.06 286.11,67.31 236.58,67.31 233.15,69.27 233.15,68 233.15,66.73 233.15,65.46 234.29,69.27 234.29,68 234.29,66.73 234.29,65.46 240.01,65.46 238.86,65.46 238.86,66.73 240.01,66.73 240.01,68 238.86,68 238.86,69.27 240.01,69.27 282.68,69.27 282.68,68 282.68,66.73 282.68,65.46 283.82,69.27 283.82,68 283.82,66.73 283.82,65.46 288.52,69.27 288.52,68 288.52,66.73 288.52,65.46 289.66,69.27 289.66,68 289.66,66.73 289.66,65.46
  pour Bottom: 0,389.23 314,389.23 314,55.85 209.78,55.85 209.78,77.24 11.66,77.24 11.66,55.88 0,55.88 0,77.24
  pour Top: 0,389.23 314,389.23 314,55.85 209.78,55.85 209.78,77.24 11.66,77.24 11.66,55.88 0,55.88 0,77.24
GND1  (via drill 0.5)
  other vias: 46.46,72.64 45.95,67.01 43.23,63.63 58.65,67.82
  pour Bottom: 13.69,75.18 13.69,55.88 77.06,55.88 77.06,75.18
  pour Top: 13.69,75.18 13.69,55.88 77.06,55.88 77.06,75.18
GND2
  pour Bottom: 194.54,43.18 194.54,0 278.36,0 278.36,43.18
  pour Top: 194.54,43.18 194.54,0 278.36,0 278.36,43.18
GNDA  (via drill 0.5)
  other vias: 165.2,67.59 167.82,67.59 169.62,67.59 167.16,63.47
  pour Bottom: 158.98,75.31 158.98,55.88 207.75,55.88 207.75,75.31
  pour Top: 158.98,75.31 158.98,55.88 207.75,55.88 207.75,75.31
IR  (via drill 0.5)
  Top 0.254: U702.1 302.49,123.82 301.6,124.71 255.75,124.71 v247.88,116.84
  Bottom 0.254: U704.64 232.93,102.27 233.3,102.64 233.3,106.49 235.65,108.84 242.42,108.84 247.88,114.3 v247.88,116.84
KEY0
  Bottom 0.254: J702.8 218.67,72.14 222.53,75.99 U704.30
KEY1
  Bottom 0.254: J702.9 217.4,71.75 221.72,76.08 U704.31
KEY2
  Bottom 0.254: J702.10 216.13,71.37 220.93,76.17 U704.32
KEY3
  Bottom 0.254: J702.11 214.86,71.12 219.12,75.38 U704.33
LDR  (via drill 0.5)
  Top 0.254: v264.52,123.7 257.28,123.7 v250.42,116.84
  Bottom 0.254: R708.1 277.99,123.89 C705.1 R705.2 264.71,123.89 v264.52,123.7 | U704.63 232.12,102.28 232.59,102.74 232.59,106.52 235.39,109.32 242.14,109.32 247.12,114.3 247.12,117.22 247.75,117.86 249.4,117.86 v250.42,116.84
LED0@U1  (via drill 0.5)
  Top 0.406: v140.44,364.87 138.79,363.22 23.98,363.22 18.52,368.68 18.52,369.57 D101.C
  Bottom 0.254: U101.2 141.25,362.71 140.44,363.53 v140.44,364.87
LED0@U2  (via drill 0.5)
  Top 0.406: v140.44,302.87 138.79,301.22 23.98,301.22 18.52,306.68 18.52,307.57 D201.C
  Bottom 0.254: U201.2 141.25,300.71 140.44,301.52 v140.44,302.87
LED0@U3  (via drill 0.5)
  Top 0.406: v140.44,240.87 138.79,239.22 23.98,239.22 18.52,244.68 18.52,245.57 D301.C
  Bottom 0.254: U301.2 141.25,238.71 140.44,239.52 v140.44,240.87
LED0@U4  (via drill 0.5)
  Top 0.406: v140.44,178.87 138.79,177.22 23.98,177.22 18.52,182.68 18.52,183.57 D401.C
  Bottom 0.254: U401.2 141.25,176.71 140.44,177.52 v140.44,178.87
LED0@U5  (via drill 0.5)
  Top 0.406: v140.44,116.87 138.79,115.22 23.98,115.22 18.52,120.68 18.52,121.57 D501.C
  Bottom 0.254: U501.2 141.25,114.71 140.44,115.52 v140.44,116.87
LED1@U1  (via drill 0.5)
  Top 0.406: v141.2,364.11 141.2,365.51 140.95,365.76 140.06,365.76 138.28,363.98 51.28,363.98 46.59,368.68 46.59,369.57 D102.C
  Bottom 0.254: U101.3 141.75,362.95 141.2,363.5 v141.2,364.11
LED1@U2  (via drill 0.5)
  Top 0.406: v141.2,302.11 141.2,303.51 140.95,303.76 140.06,303.76 138.28,301.98 51.28,301.98 46.59,306.68 46.59,307.57 D202.C
  Bottom 0.254: U201.3 141.75,300.95 141.2,301.5 v141.2,302.11
LED1@U3  (via drill 0.5)
  Top 0.406: v141.2,240.11 141.2,241.51 140.95,241.76 140.06,241.76 138.28,239.98 51.28,239.98 46.59,244.68 46.59,245.57 D302.C
  Bottom 0.254: U301.3 141.75,238.95 141.2,239.5 v141.2,240.11
LED1@U4  (via drill 0.5)
  Top 0.406: v141.2,178.11 141.2,179.51 140.95,179.76 140.06,179.76 138.28,177.98 51.28,177.98 46.59,182.68 46.59,183.57 D402.C
  Bottom 0.254: U401.3 141.75,176.95 141.2,177.5 v141.2,178.11
LED1@U5  (via drill 0.5)
  Top 0.406: v141.2,116.11 141.2,117.51 140.95,117.76 140.06,117.76 138.28,115.98 51.28,115.98 46.59,120.68 46.59,121.57 D502.C
  Bottom 0.254: U501.3 141.75,114.95 141.2,115.5 v141.2,116.11
LED2@U1  (via drill 0.5)
  Top 0.406: v141.96,364.87 141.96,365.89 141.33,366.52 139.55,366.52 137.77,364.74 78.59,364.74 74.78,368.55 74.78,369.51 D103.C
  Bottom 0.254: U101.4 142.25,363.19 141.96,363.47 v141.96,364.87
LED2@U2  (via drill 0.5)
  Top 0.406: v141.96,302.87 141.96,303.89 141.33,304.52 139.55,304.52 137.77,302.74 78.59,302.74 74.78,306.55 74.78,307.51 D203.C
  Bottom 0.254: U201.4 142.25,301.19 141.96,301.47 v141.96,302.87
LED2@U3  (via drill 0.5)
  Top 0.406: v141.96,240.87 141.96,241.89 141.33,242.52 139.55,242.52 137.77,240.74 78.59,240.74 74.78,244.55 74.78,245.51 D303.C
  Bottom 0.254: U301.4 142.25,239.19 141.96,239.47 v141.96,240.87
LED2@U4  (via drill 0.5)
  Top 0.406: v141.96,178.87 141.96,179.89 141.33,180.52 139.55,180.52 137.77,178.74 78.59,178.74 74.78,182.55 74.78,183.51 D403.C
  Bottom 0.254: U401.4 142.25,177.19 141.96,177.47 v141.96,178.87
LED2@U5  (via drill 0.5)
  Top 0.406: v141.96,116.87 141.96,117.89 141.33,118.52 139.55,118.52 137.77,116.74 78.59,116.74 74.78,120.55 74.78,121.51 D503.C
  Bottom 0.254: U501.4 142.25,115.19 141.96,115.47 v141.96,116.87
LED3@U1  (via drill 0.5)
  Top 0.406: v142.72,364.11 142.72,366.27 141.71,367.28 139.04,367.28 137.26,365.51 105.89,365.51 102.85,368.55 102.85,369.54 D104.C
  Bottom 0.254: U101.5 142.75,364.08 v142.72,364.11
LED3@U2  (via drill 0.5)
  Top 0.406: v142.72,302.11 142.72,304.27 141.71,305.28 139.04,305.28 137.26,303.51 105.89,303.51 102.85,306.55 102.85,307.54 D204.C
  Bottom 0.254: U201.5 142.75,302.08 v142.72,302.11
LED3@U3  (via drill 0.5)
  Top 0.406: v142.72,240.11 142.72,242.27 141.71,243.28 139.04,243.28 137.26,241.51 105.89,241.51 102.85,244.55 102.85,245.54 D304.C
  Bottom 0.254: U301.5 142.75,240.08 v142.72,240.11
LED3@U4  (via drill 0.5)
  Top 0.406: v142.72,178.11 142.72,180.27 141.71,181.28 139.04,181.28 137.26,179.51 105.89,179.51 102.85,182.55 102.85,183.54 D404.C
  Bottom 0.254: U401.5 142.75,178.08 v142.72,178.11
LED3@U5  (via drill 0.5)
  Top 0.406: v142.72,116.11 142.72,118.27 141.71,119.28 139.04,119.28 137.26,117.51 105.89,117.51 102.85,120.55 102.85,121.54 D504.C
  Bottom 0.254: U501.5 142.75,116.08 v142.72,116.11
LED4@U1  (via drill 0.5)
  Top 0.406: D105.C 141.18,369.59 144.25,366.52 v144.25,364.87
  Bottom 0.254: U101.8 v144.25,364.87
LED4@U2  (via drill 0.5)
  Top 0.406: D205.C 141.18,307.59 144.25,304.52 v144.25,302.87
  Bottom 0.254: U201.8 v144.25,302.87
LED4@U3  (via drill 0.5)
  Top 0.406: D305.C 141.18,245.59 144.25,242.52 v144.25,240.87
  Bottom 0.254: U301.8 v144.25,240.87
LED4@U4  (via drill 0.5)
  Top 0.406: D405.C 141.18,183.59 144.25,180.52 v144.25,178.87
  Bottom 0.254: U401.8 v144.25,178.87
LED4@U5  (via drill 0.5)
  Top 0.406: D505.C 141.18,121.59 144.25,118.52 v144.25,116.87
  Bottom 0.254: U501.8 v144.25,116.87
LED5@U1  (via drill 0.5)
  Top 0.406: v145.01,364.11 145.01,365.76 145.77,366.52 156.97,366.52 158.98,368.53 158.98,369.57 D106.C
  Bottom 0.254: U101.9 144.75,363.85 v145.01,364.11
LED5@U2  (via drill 0.5)
  Top 0.406: v145.01,302.11 145.01,303.76 145.77,304.52 156.97,304.52 158.98,306.53 158.98,307.57 D206.C
  Bottom 0.254: U201.9 144.75,301.85 v145.01,302.11
LED5@U3  (via drill 0.5)
  Top 0.406: v145.01,240.11 145.01,241.76 145.77,242.52 156.97,242.52 158.98,244.53 158.98,245.57 D306.C
  Bottom 0.254: U301.9 144.75,239.85 v145.01,240.11
LED5@U4  (via drill 0.5)
  Top 0.406: v145.01,178.11 145.01,179.76 145.77,180.52 156.97,180.52 158.98,182.53 158.98,183.57 D406.C
  Bottom 0.254: U401.9 144.75,177.85 v145.01,178.11
LED5@U5  (via drill 0.5)
  Top 0.406: v145.01,116.11 145.01,117.76 145.77,118.52 156.97,118.52 158.98,120.53 158.98,121.57 D506.C
  Bottom 0.254: U501.9 144.75,115.85 v145.01,116.11
LED6@U1  (via drill 0.5)
  Top 0.406: v145.77,364.87 146.66,365.76 184.3,365.76 187.1,368.55 D107.C
  Bottom 0.254: U101.10 145.25,363.28 145.77,363.8 v145.77,364.87
LED6@U2  (via drill 0.5)
  Top 0.406: v145.77,302.87 146.66,303.76 184.3,303.76 187.1,306.55 D207.C
  Bottom 0.254: U201.10 145.25,301.28 145.77,301.8 v145.77,302.87
LED6@U3  (via drill 0.5)
  Top 0.406: v145.77,240.87 146.66,241.76 184.3,241.76 187.1,244.55 D307.C
  Bottom 0.254: U301.10 145.25,239.28 145.77,239.8 v145.77,240.87
LED6@U4  (via drill 0.5)
  Top 0.406: v145.77,178.87 146.66,179.76 184.3,179.76 187.1,182.55 D407.C
  Bottom 0.254: U401.10 145.25,177.28 145.77,177.8 v145.77,178.87
LED6@U5  (via drill 0.5)
  Top 0.406: v145.77,116.87 146.66,117.76 184.3,117.76 187.1,120.55 D507.C
  Bottom 0.254: U501.10 145.25,115.28 145.77,115.8 v145.77,116.87
LED7@U1  (via drill 0.5)
  Top 0.406: v146.66,364.11 147.55,365 211.63,365 215.22,368.58 215.22,369.57 D108.C
  Bottom 0.254: U101.11 145.75,363.02 146.66,363.93 v146.66,364.11
LED7@U2  (via drill 0.5)
  Top 0.406: v146.66,302.11 147.55,303 211.63,303 215.22,306.58 215.22,307.57 D208.C
  Bottom 0.254: U201.11 145.75,301.02 146.66,301.93 v146.66,302.11
LED7@U3  (via drill 0.5)
  Top 0.406: v146.66,240.11 147.55,241 211.63,241 215.22,244.58 215.22,245.57 D308.C
  Bottom 0.254: U301.11 145.75,239.02 146.66,239.93 v146.66,240.11
LED7@U4  (via drill 0.5)
  Top 0.406: v146.66,178.11 147.55,179 211.63,179 215.22,182.58 215.22,183.57 D408.C
  Bottom 0.254: U401.11 145.75,177.02 146.66,177.93 v146.66,178.11
LED7@U5  (via drill 0.5)
  Top 0.406: v146.66,116.11 147.55,117 211.63,117 215.22,120.58 215.22,121.57 D508.C
  Bottom 0.254: U501.11 145.75,115.02 146.66,115.93 v146.66,116.11
LED8@U1  (via drill 0.5)
  Top 0.406: v150.6,359.03 155.81,364.24 238.99,364.24 243.31,368.55 D109.C
  Bottom 0.254: U101.17 149.04,358.49 149.58,359.03 v150.6,359.03
LED8@U2  (via drill 0.5)
  Top 0.406: v150.6,297.03 155.81,302.24 238.99,302.24 243.31,306.55 D209.C
  Bottom 0.254: U201.17 149.04,296.49 149.58,297.03 v150.6,297.03
LED8@U3  (via drill 0.5)
  Top 0.406: v150.6,235.03 155.81,240.24 238.99,240.24 243.31,244.55 D309.C
  Bottom 0.254: U301.17 149.04,234.49 149.58,235.03 v150.6,235.03
LED8@U4  (via drill 0.5)
  Top 0.406: v150.6,173.03 155.81,178.24 238.99,178.24 243.31,182.55 D409.C
  Bottom 0.254: U401.17 149.04,172.49 149.58,173.03 v150.6,173.03
LED8@U5  (via drill 0.5)
  Top 0.406: v150.6,111.03 155.81,116.24 238.99,116.24 243.31,120.55 D509.C
  Bottom 0.254: U501.17 149.04,110.49 149.58,111.03 v150.6,111.03
LED9@U1  (via drill 0.5)
  Top 0.406: v149.84,358.14 150.98,358.14 156.31,363.47 266.3,363.47 271.25,368.43 271.25,369.44 D110.C
  Bottom 0.254: U101.18 149.69,357.99 v149.84,358.14
LED9@U2  (via drill 0.5)
  Top 0.406: v149.84,296.14 150.98,296.14 156.31,301.47 266.3,301.47 271.25,306.43 271.25,307.44 D210.C
  Bottom 0.254: U201.18 149.69,295.99 v149.84,296.14
LED9@U3  (via drill 0.5)
  Top 0.406: v149.84,234.14 150.98,234.14 156.31,239.47 266.3,239.47 271.25,244.43 271.25,245.44 D310.C
  Bottom 0.254: U301.18 149.69,233.99 v149.84,234.14
LED9@U4  (via drill 0.5)
  Top 0.406: v149.84,172.14 150.98,172.14 156.31,177.47 266.3,177.47 271.25,182.43 271.25,183.44 D410.C
  Bottom 0.254: U401.18 149.69,171.99 v149.84,172.14
LED9@U5  (via drill 0.5)
  Top 0.406: v149.84,110.14 150.98,110.14 156.31,115.47 266.3,115.47 271.25,120.43 271.25,121.44 D510.C
  Bottom 0.254: U501.18 149.69,109.99 v149.84,110.14
LED10@U1  (via drill 0.5)
  Top 0.406: v150.6,357.25 151.36,357.25 156.82,362.71 293.6,362.71 299.44,368.55 299.44,369.53 D111.C
  Bottom 0.254: U101.19 149.5,357.49 149.73,357.25 v150.6,357.25
LED10@U2  (via drill 0.5)
  Top 0.406: v150.6,295.25 151.36,295.25 156.82,300.71 293.6,300.71 299.44,306.55 299.44,307.53 D211.C
  Bottom 0.254: U201.19 149.5,295.49 149.73,295.25 v150.6,295.25
LED10@U3  (via drill 0.5)
  Top 0.406: v150.6,233.25 151.36,233.25 156.82,238.71 293.6,238.71 299.44,244.55 299.44,245.53 D311.C
  Bottom 0.254: U301.19 149.5,233.49 149.73,233.25 v150.6,233.25
LED10@U4  (via drill 0.5)
  Top 0.406: v150.6,171.25 151.36,171.25 156.82,176.71 293.6,176.71 299.44,182.55 299.44,183.53 D411.C
  Bottom 0.254: U401.19 149.5,171.49 149.73,171.25 v150.6,171.25
LED10@U5  (via drill 0.5)
  Top 0.406: v150.6,109.25 151.36,109.25 156.82,114.71 293.6,114.71 299.44,120.55 299.44,121.53 D511.C
  Bottom 0.254: U501.19 149.5,109.49 149.73,109.25 v150.6,109.25
LED11@U1  (via drill 0.5)
  Top 0.406: D122.C 295.5,345.82 289.41,351.92 157.84,351.92 153.26,356.49 v149.84,356.49
  Bottom 0.254: U101.20 149.34,356.99 v149.84,356.49
LED11@U2  (via drill 0.5)
  Top 0.406: D222.C 295.5,283.82 289.41,289.92 160.91,289.92 156.34,294.49 v149.84,294.49
  Bottom 0.254: U201.20 149.34,294.99 v149.84,294.49
LED11@U3  (via drill 0.5)
  Top 0.406: D322.C 295.5,221.82 289.41,227.92 158.82,227.92 154.25,232.49 v149.84,232.49
  Bottom 0.254: U301.20 149.34,232.99 v149.84,232.49
LED11@U4  (via drill 0.5)
  Top 0.406: D422.C 295.5,159.82 289.41,165.92 160.7,165.92 156.13,170.49 v149.84,170.49
  Bottom 0.254: U401.20 149.34,170.99 v149.84,170.49
LED11@U5  (via drill 0.5)
  Top 0.406: D522.C 295.5,112.01 293.6,113.92 157.33,113.92 151.9,108.49 v149.84,108.49
  Bottom 0.254: U501.20 149.34,108.99 v149.84,108.49
LED12@U1  (via drill 0.5)
  Top 0.406: D121.C 267.44,344.93 267.44,345.44 261.72,351.16 146.79,351.16 v146.53,351.41
  Bottom 0.254: U101.26 145.75,352.45 146.53,351.66 v146.53,351.41
LED12@U2  (via drill 0.5)
  Top 0.406: D221.C 267.44,282.93 267.44,283.44 261.72,289.15 146.79,289.15 v146.53,289.41
  Bottom 0.254: U201.26 145.75,290.45 146.53,289.66 v146.53,289.41
LED12@U3  (via drill 0.5)
  Top 0.406: D321.C 267.44,220.93 267.44,221.44 261.72,227.15 146.79,227.15 v146.53,227.41
  Bottom 0.254: U301.26 145.75,228.45 146.53,227.66 v146.53,227.41
LED12@U4  (via drill 0.5)
  Top 0.406: D421.C 267.44,158.93 267.44,159.44 261.72,165.16 146.79,165.16 v146.53,165.41
  Bottom 0.254: U401.26 145.75,166.45 146.53,165.66 v146.53,165.41
LED12@U5  (via drill 0.5)
  Top 0.406: D521.C 267.44,96.93 267.44,110.49 264.77,113.16 157.84,113.16 155.55,110.87 155.55,104.77 153.93,103.16 146.79,103.16 v146.53,103.41
  Bottom 0.254: U501.26 145.75,104.45 146.53,103.66 v146.53,103.41
LED13@U1  (via drill 0.5)
  Top 0.406: v145.77,350.65 146.03,350.39 234.29,350.39 238.86,345.82 238.86,345.33 D120.C
  Bottom 0.254: U101.27 145.25,352.19 145.77,351.66 v145.77,350.65
LED13@U2  (via drill 0.5)
  Top 0.406: v145.77,288.65 146.03,288.39 234.29,288.39 238.86,283.82 238.86,283.33 D220.C
  Bottom 0.254: U201.27 145.25,290.19 145.77,289.66 v145.77,288.65
LED13@U3  (via drill 0.5)
  Top 0.406: v145.77,226.65 146.03,226.39 234.29,226.39 238.86,221.82 238.86,221.33 D320.C
  Bottom 0.254: U301.27 145.25,228.19 145.77,227.66 v145.77,226.65
LED13@U4  (via drill 0.5)
  Top 0.406: v145.77,164.65 146.03,164.39 234.29,164.39 238.86,159.82 238.86,159.33 D420.C
  Bottom 0.254: U401.27 145.25,166.19 145.77,165.66 v145.77,164.65
LED13@U5  (via drill 0.5)
  Top 0.406: v145.77,102.65 146.03,102.39 154.44,102.39 156.44,104.39 156.44,110.49 158.34,112.39 237.59,112.39 239.3,110.69 D520.C
  Bottom 0.254: U501.27 145.25,104.19 145.77,103.66 v145.77,102.65
LED14@U1  (via drill 0.5)
  Top 0.406: v145.01,351.41 145.01,350.14 145.52,349.63 207.11,349.63 211.18,345.57 211.18,344.91 D119.C
  Bottom 0.254: U101.28 144.75,351.67 v145.01,351.41
LED14@U2  (via drill 0.5)
  Top 0.406: v145.01,289.41 145.01,288.14 145.52,287.63 207.11,287.63 211.18,283.57 211.18,282.91 D219.C
  Bottom 0.254: U201.28 144.75,289.67 v145.01,289.41
LED14@U3  (via drill 0.5)
  Top 0.406: v145.01,227.41 145.01,226.14 145.52,225.63 207.11,225.63 211.18,221.57 211.18,220.91 D319.C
